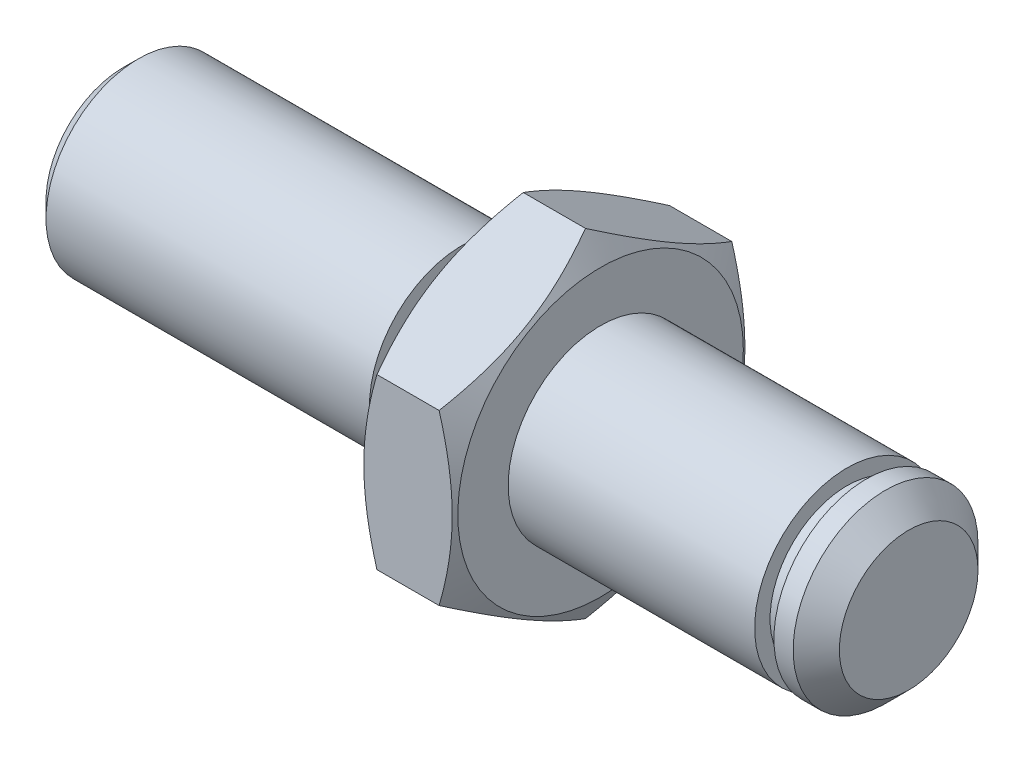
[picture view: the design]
ISO-10303-21;
HEADER;
FILE_DESCRIPTION(('STEP AP214'),'2;1');
FILE_NAME('part.step','',(''),(''),'','','');
FILE_SCHEMA(('AUTOMOTIVE_DESIGN { 1 0 10303 214 1 1 1 1 }'));
ENDSEC;
DATA;
#1=APPLICATION_CONTEXT('core data for automotive mechanical design processes');
#2=APPLICATION_PROTOCOL_DEFINITION('international standard','automotive_design',2000,#1);
#3=PRODUCT_CONTEXT('',#1,'mechanical');
#4=PRODUCT('Part','Part','',(#3));
#5=PRODUCT_RELATED_PRODUCT_CATEGORY('part','',(#4));
#6=PRODUCT_DEFINITION_FORMATION('','',#4);
#7=PRODUCT_DEFINITION_CONTEXT('part definition',#1,'design');
#8=PRODUCT_DEFINITION('design','',#6,#7);
#9=PRODUCT_DEFINITION_SHAPE('','',#8);
#10=(LENGTH_UNIT() NAMED_UNIT(*) SI_UNIT(.MILLI.,.METRE.));
#11=(NAMED_UNIT(*) PLANE_ANGLE_UNIT() SI_UNIT($,.RADIAN.));
#12=(NAMED_UNIT(*) SI_UNIT($,.STERADIAN.) SOLID_ANGLE_UNIT());
#13=UNCERTAINTY_MEASURE_WITH_UNIT(LENGTH_MEASURE(1.E-05),#10,'distance_accuracy_value','');
#14=(GEOMETRIC_REPRESENTATION_CONTEXT(3) GLOBAL_UNCERTAINTY_ASSIGNED_CONTEXT((#13)) GLOBAL_UNIT_ASSIGNED_CONTEXT((#10,
#11,#12)) REPRESENTATION_CONTEXT('',''));
#15=CARTESIAN_POINT('',(0.,0.,0.));
#16=DIRECTION('',(0.,0.,1.));
#17=DIRECTION('',(1.,0.,0.));
#18=AXIS2_PLACEMENT_3D('',#15,#16,#17);
#19=CARTESIAN_POINT('',(31.,0.,0.));
#20=DIRECTION('',(-1.,0.,0.));
#21=DIRECTION('',(0.,0.,1.));
#22=AXIS2_PLACEMENT_3D('',#19,#20,#21);
#23=CONICAL_SURFACE('',#22,9.26794919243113,1.0471975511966);
#24=CARTESIAN_POINT('',(31.,0.,0.));
#25=DIRECTION('',(1.,0.,0.));
#26=DIRECTION('',(0.,0.,-1.));
#27=AXIS2_PLACEMENT_3D('',#24,#25,#26);
#28=CIRCLE('',#27,9.26794919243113);
#29=CARTESIAN_POINT('',(31.,0.,-9.26794919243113));
#30=VERTEX_POINT('',#29);
#31=EDGE_CURVE('E254',#30,#30,#28,.T.);
#32=ORIENTED_EDGE('',*,*,#31,.F.);
#33=EDGE_LOOP('',(#32));
#34=FACE_BOUND('',#33,.T.);
#35=CARTESIAN_POINT('',(30.0174529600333,-5.4847120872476,9.5002));
#36=CARTESIAN_POINT('',(30.0870519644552,-5.60528058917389,9.2913692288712));
#37=CARTESIAN_POINT('',(30.1534920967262,-5.72629863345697,9.08175982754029));
#38=CARTESIAN_POINT('',(30.2791781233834,-5.96930519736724,8.66086011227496));
#39=CARTESIAN_POINT('',(30.3384216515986,-6.09129402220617,8.44956926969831));
#40=CARTESIAN_POINT('',(30.5042108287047,-6.45922610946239,7.81229220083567));
#41=CARTESIAN_POINT('',(30.598510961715,-6.70662183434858,7.38379023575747));
#42=CARTESIAN_POINT('',(30.7090866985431,-7.07683821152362,6.74255666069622));
#43=CARTESIAN_POINT('',(30.7405855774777,-7.19855281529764,6.5317407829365));
#44=CARTESIAN_POINT('',(30.7934072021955,-7.44254555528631,6.10913296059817));
#45=CARTESIAN_POINT('',(30.8147297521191,-7.56482370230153,5.89734099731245));
#46=CARTESIAN_POINT('',(30.8466523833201,-7.80958396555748,5.4734037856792));
#47=CARTESIAN_POINT('',(30.8572652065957,-7.93206566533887,5.26125925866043));
#48=CARTESIAN_POINT('',(30.8675428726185,-8.17714220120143,4.83677424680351));
#49=CARTESIAN_POINT('',(30.867208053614,-8.29973703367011,4.62443376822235));
#50=CARTESIAN_POINT('',(30.8563520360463,-8.5289310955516,4.22745800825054));
#51=CARTESIAN_POINT('',(30.8471551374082,-8.63554650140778,4.04279470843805));
#52=CARTESIAN_POINT('',(30.8206600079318,-8.84852796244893,3.67389999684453));
#53=CARTESIAN_POINT('',(30.8033612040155,-8.95489399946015,3.48966861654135));
#54=CARTESIAN_POINT('',(30.7397209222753,-9.27357996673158,2.93768832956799));
#55=CARTESIAN_POINT('',(30.6816435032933,-9.48533580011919,2.57091646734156));
#56=CARTESIAN_POINT('',(30.5364493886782,-9.91109368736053,1.83348217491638));
#57=CARTESIAN_POINT('',(30.448717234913,-10.1250414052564,1.46291385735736));
#58=CARTESIAN_POINT('',(30.2496016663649,-10.5497463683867,0.727303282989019));
#59=CARTESIAN_POINT('',(30.1382650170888,-10.7605090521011,0.362251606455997));
#60=CARTESIAN_POINT('',(30.0174529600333,-10.9697705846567,-0.000200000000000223));
#61=B_SPLINE_CURVE_WITH_KNOTS('',3,(#35,#36,#37,#38,#39,#40,#41,#42,#43,#44,#45,#46,#47,#48,#49,
#50,#51,#52,#53,#54,#55,#56,#57,#58,#59,#60),.UNSPECIFIED.,.F.,.F.,(4,2,2,2,2,2,2,2,2,2,2,2,4),
(0.,0.752880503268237,1.50600787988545,3.0154687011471,3.75167336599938,4.48789219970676,
5.22323407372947,5.95855322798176,6.59868084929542,7.23885375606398,8.52010929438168,
9.82978009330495,11.1368800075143),.UNSPECIFIED.);
#62=CARTESIAN_POINT('',(30.0175196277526,-5.48482755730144,9.49999999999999));
#63=VERTEX_POINT('',#62);
#64=CARTESIAN_POINT('',(30.0175196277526,-10.9696551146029,0.));
#65=VERTEX_POINT('',#64);
#66=EDGE_CURVE('E48',#63,#65,#61,.T.);
#67=ORIENTED_EDGE('',*,*,#66,.T.);
#68=CARTESIAN_POINT('',(30.0174529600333,-10.9697705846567,0.000199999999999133));
#69=CARTESIAN_POINT('',(30.0870519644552,-10.8492020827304,-0.208630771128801));
#70=CARTESIAN_POINT('',(30.1534920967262,-10.7281840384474,-0.41824017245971));
#71=CARTESIAN_POINT('',(30.2791781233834,-10.4851774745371,-0.839139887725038));
#72=CARTESIAN_POINT('',(30.3384216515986,-10.3631886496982,-1.05043073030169));
#73=CARTESIAN_POINT('',(30.5042108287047,-9.99525656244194,-1.68770779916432));
#74=CARTESIAN_POINT('',(30.598510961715,-9.74786083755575,-2.11620976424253));
#75=CARTESIAN_POINT('',(30.7090866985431,-9.37764446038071,-2.75744333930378));
#76=CARTESIAN_POINT('',(30.7405855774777,-9.25592985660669,-2.96825921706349));
#77=CARTESIAN_POINT('',(30.7934072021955,-9.01193711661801,-3.39086703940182));
#78=CARTESIAN_POINT('',(30.8147297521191,-8.8896589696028,-3.60265900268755));
#79=CARTESIAN_POINT('',(30.8466523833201,-8.64489870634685,-4.0265962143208));
#80=CARTESIAN_POINT('',(30.8572652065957,-8.52241700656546,-4.23874074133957));
#81=CARTESIAN_POINT('',(30.8675428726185,-8.2773404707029,-4.66322575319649));
#82=CARTESIAN_POINT('',(30.867208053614,-8.15474563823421,-4.87556623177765));
#83=CARTESIAN_POINT('',(30.8563520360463,-7.92555157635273,-5.27254199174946));
#84=CARTESIAN_POINT('',(30.8471551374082,-7.81893617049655,-5.45720529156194));
#85=CARTESIAN_POINT('',(30.8206600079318,-7.6059547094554,-5.82610000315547));
#86=CARTESIAN_POINT('',(30.8033612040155,-7.49958867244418,-6.01033138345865));
#87=CARTESIAN_POINT('',(30.7397209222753,-7.18090270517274,-6.56231167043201));
#88=CARTESIAN_POINT('',(30.6816435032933,-6.96914687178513,-6.92908353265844));
#89=CARTESIAN_POINT('',(30.5364493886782,-6.5433889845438,-7.66651782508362));
#90=CARTESIAN_POINT('',(30.448717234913,-6.32944126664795,-8.03708614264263));
#91=CARTESIAN_POINT('',(30.2496016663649,-5.90473630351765,-8.77269671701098));
#92=CARTESIAN_POINT('',(30.1382650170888,-5.69397361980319,-9.137748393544));
#93=CARTESIAN_POINT('',(30.0174529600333,-5.48471208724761,-9.5002));
#94=B_SPLINE_CURVE_WITH_KNOTS('',3,(#68,#69,#70,#71,#72,#73,#74,#75,#76,#77,#78,#79,#80,#81,#82,
#83,#84,#85,#86,#87,#88,#89,#90,#91,#92,#93),.UNSPECIFIED.,.F.,.F.,(4,2,2,2,2,2,2,2,2,2,2,2,4),
(0.,0.752880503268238,1.50600787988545,3.0154687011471,3.75167336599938,4.48789219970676,
5.22323407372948,5.95855322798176,6.59868084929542,7.23885375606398,8.52010929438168,
9.82978009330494,11.1368800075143),.UNSPECIFIED.);
#95=CARTESIAN_POINT('',(30.0175196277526,-5.48482755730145,-9.5));
#96=VERTEX_POINT('',#95);
#97=EDGE_CURVE('E11',#65,#96,#94,.T.);
#98=ORIENTED_EDGE('',*,*,#97,.T.);
#99=CARTESIAN_POINT('',(26.3278254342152,-14.530424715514,-9.5));
#100=CARTESIAN_POINT('',(26.4285687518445,-14.3219433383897,-9.5));
#101=CARTESIAN_POINT('',(26.5287893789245,-14.1132095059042,-9.5));
#102=CARTESIAN_POINT('',(26.7280652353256,-13.6951836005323,-9.5));
#103=CARTESIAN_POINT('',(26.8271204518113,-13.4858915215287,-9.5));
#104=CARTESIAN_POINT('',(27.1223867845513,-12.8570363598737,-9.5));
#105=CARTESIAN_POINT('',(27.3166656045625,-12.4365624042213,-9.5));
#106=CARTESIAN_POINT('',(27.6999280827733,-11.5902889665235,-9.5));
#107=CARTESIAN_POINT('',(27.8888749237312,-11.1644727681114,-9.5));
#108=CARTESIAN_POINT('',(28.2586328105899,-10.3093352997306,-9.5));
#109=CARTESIAN_POINT('',(28.4394442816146,-9.88001421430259,-9.5));
#110=CARTESIAN_POINT('',(28.7928780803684,-9.01192846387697,-9.5));
#111=CARTESIAN_POINT('',(28.9653748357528,-8.57311238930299,-9.5));
#112=CARTESIAN_POINT('',(29.2968184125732,-7.69029988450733,-9.5));
#113=CARTESIAN_POINT('',(29.4557637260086,-7.24630288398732,-9.5));
#114=CARTESIAN_POINT('',(29.7558208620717,-6.35333393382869,-9.5));
#115=CARTESIAN_POINT('',(29.8969707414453,-5.90437491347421,-9.5));
#116=CARTESIAN_POINT('',(30.1568449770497,-5.0000911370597,-9.5));
#117=CARTESIAN_POINT('',(30.275576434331,-4.54476844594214,-9.5));
#118=CARTESIAN_POINT('',(30.4848321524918,-3.62736382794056,-9.5));
#119=CARTESIAN_POINT('',(30.5753480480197,-3.16527993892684,-9.5));
#120=CARTESIAN_POINT('',(30.6854186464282,-2.46810217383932,-9.5));
#121=CARTESIAN_POINT('',(30.7178273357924,-2.23500583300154,-9.5));
#122=CARTESIAN_POINT('',(30.7734391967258,-1.76772497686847,-9.5));
#123=CARTESIAN_POINT('',(30.7966432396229,-1.533540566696,-9.5));
#124=CARTESIAN_POINT('',(30.8332219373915,-1.06587755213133,-9.5));
#125=CARTESIAN_POINT('',(30.8466572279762,-0.832403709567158,-9.5));
#126=CARTESIAN_POINT('',(30.8636276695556,-0.365097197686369,-9.5));
#127=CARTESIAN_POINT('',(30.867162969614,-0.131264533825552,-9.5));
#128=CARTESIAN_POINT('',(30.8642492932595,0.336274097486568,-9.5));
#129=CARTESIAN_POINT('',(30.8578031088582,0.569980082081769,-9.5));
#130=CARTESIAN_POINT('',(30.8350863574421,1.03691732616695,-9.5));
#131=CARTESIAN_POINT('',(30.8188152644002,1.27014855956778,-9.5));
#132=CARTESIAN_POINT('',(30.7677796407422,1.83577635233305,-9.5));
#133=CARTESIAN_POINT('',(30.7280735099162,2.16773568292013,-9.5));
#134=CARTESIAN_POINT('',(30.6309725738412,2.82904294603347,-9.5));
#135=CARTESIAN_POINT('',(30.5735751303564,3.15839048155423,-9.5));
#136=CARTESIAN_POINT('',(30.3777256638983,4.14309533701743,-9.5));
#137=CARTESIAN_POINT('',(30.2157474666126,4.79382711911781,-9.5));
#138=CARTESIAN_POINT('',(29.9365826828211,5.76718145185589,-9.5));
#139=CARTESIAN_POINT('',(29.8361342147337,6.09489303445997,-9.5));
#140=CARTESIAN_POINT('',(29.6252534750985,6.74715044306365,-9.5));
#141=CARTESIAN_POINT('',(29.5148203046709,7.0716959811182,-9.5));
#142=CARTESIAN_POINT('',(29.2863341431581,7.71600141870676,-9.5));
#143=CARTESIAN_POINT('',(29.1683276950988,8.03577799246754,-9.5));
#144=CARTESIAN_POINT('',(28.9255004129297,8.67261160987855,-9.5));
#145=CARTESIAN_POINT('',(28.8006819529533,8.98966955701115,-9.5));
#146=CARTESIAN_POINT('',(28.6730955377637,9.30558311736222,-9.5));
#147=B_SPLINE_CURVE_WITH_KNOTS('',3,(#99,#100,#101,#102,#103,#104,#105,#106,#107,#108,#109,#110,
#111,#112,#113,#114,#115,#116,#117,#118,#119,#120,#121,#122,#123,#124,#125,#126,#127,#128,#129,
#130,#131,#132,#133,#134,#135,#136,#137,#138,#139,#140,#141,#142,#143,#144,#145,#146),
.UNSPECIFIED.,.F.,.F.,(4,2,2,2,2,2,2,2,2,2,2,2,2,2,2,2,2,2,2,2,2,2,2,4),(0.,0.694637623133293,
1.38928288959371,2.77880027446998,4.17629754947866,5.57372171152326,6.98805594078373,
8.40254735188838,9.81396052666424,11.2249258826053,12.6363091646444,13.3421715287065,
14.0479670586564,14.7493433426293,15.4507090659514,16.1518786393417,16.8530857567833,
17.8554925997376,18.8580490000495,20.867027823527,21.8952298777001,22.9235245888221,
23.9460134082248,24.9681481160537),.UNSPECIFIED.);
#148=CARTESIAN_POINT('',(30.0175196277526,5.48482755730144,-9.5));
#149=VERTEX_POINT('',#148);
#150=EDGE_CURVE('E149',#96,#149,#147,.T.);
#151=ORIENTED_EDGE('',*,*,#150,.T.);
#152=CARTESIAN_POINT('',(30.0174529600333,5.4847120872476,-9.5002));
#153=CARTESIAN_POINT('',(30.0870519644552,5.6052805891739,-9.2913692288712));
#154=CARTESIAN_POINT('',(30.1534920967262,5.72629863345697,-9.08175982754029));
#155=CARTESIAN_POINT('',(30.2791781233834,5.96930519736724,-8.66086011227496));
#156=CARTESIAN_POINT('',(30.3384216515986,6.09129402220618,-8.44956926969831));
#157=CARTESIAN_POINT('',(30.5042108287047,6.45922610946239,-7.81229220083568));
#158=CARTESIAN_POINT('',(30.598510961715,6.70662183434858,-7.38379023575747));
#159=CARTESIAN_POINT('',(30.7090866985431,7.07683821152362,-6.74255666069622));
#160=CARTESIAN_POINT('',(30.7405855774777,7.19855281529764,-6.53174078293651));
#161=CARTESIAN_POINT('',(30.7934072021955,7.44254555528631,-6.10913296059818));
#162=CARTESIAN_POINT('',(30.8147297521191,7.56482370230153,-5.89734099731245));
#163=CARTESIAN_POINT('',(30.8466523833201,7.80958396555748,-5.4734037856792));
#164=CARTESIAN_POINT('',(30.8572652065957,7.93206566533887,-5.26125925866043));
#165=CARTESIAN_POINT('',(30.8675428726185,8.17714220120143,-4.83677424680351));
#166=CARTESIAN_POINT('',(30.867208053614,8.29973703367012,-4.62443376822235));
#167=CARTESIAN_POINT('',(30.8563520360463,8.5289310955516,-4.22745800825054));
#168=CARTESIAN_POINT('',(30.8471551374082,8.63554650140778,-4.04279470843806));
#169=CARTESIAN_POINT('',(30.8206600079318,8.84852796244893,-3.67389999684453));
#170=CARTESIAN_POINT('',(30.8033612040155,8.95489399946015,-3.48966861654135));
#171=CARTESIAN_POINT('',(30.7397209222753,9.27357996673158,-2.93768832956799));
#172=CARTESIAN_POINT('',(30.6816435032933,9.48533580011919,-2.57091646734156));
#173=CARTESIAN_POINT('',(30.5364493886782,9.91109368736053,-1.83348217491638));
#174=CARTESIAN_POINT('',(30.448717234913,10.1250414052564,-1.46291385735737));
#175=CARTESIAN_POINT('',(30.2496016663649,10.5497463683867,-0.727303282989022));
#176=CARTESIAN_POINT('',(30.1382650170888,10.7605090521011,-0.362251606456));
#177=CARTESIAN_POINT('',(30.0174529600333,10.9697705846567,0.000199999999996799));
#178=B_SPLINE_CURVE_WITH_KNOTS('',3,(#152,#153,#154,#155,#156,#157,#158,#159,#160,#161,#162,
#163,#164,#165,#166,#167,#168,#169,#170,#171,#172,#173,#174,#175,#176,#177),.UNSPECIFIED.,.F.,
.F.,(4,2,2,2,2,2,2,2,2,2,2,2,4),(0.,0.752880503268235,1.50600787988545,3.0154687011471,
3.75167336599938,4.48789219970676,5.22323407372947,5.95855322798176,6.59868084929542,
7.23885375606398,8.52010929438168,9.82978009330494,11.1368800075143),.UNSPECIFIED.);
#179=CARTESIAN_POINT('',(30.0175196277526,10.9696551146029,0.));
#180=VERTEX_POINT('',#179);
#181=EDGE_CURVE('E103',#149,#180,#178,.T.);
#182=ORIENTED_EDGE('',*,*,#181,.T.);
#183=CARTESIAN_POINT('',(30.0174529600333,10.9697705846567,-0.000200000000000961));
#184=CARTESIAN_POINT('',(30.0870519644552,10.8492020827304,0.208630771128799));
#185=CARTESIAN_POINT('',(30.1534920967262,10.7281840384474,0.418240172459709));
#186=CARTESIAN_POINT('',(30.2791781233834,10.4851774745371,0.839139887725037));
#187=CARTESIAN_POINT('',(30.3384216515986,10.3631886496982,1.05043073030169));
#188=CARTESIAN_POINT('',(30.5042108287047,9.99525656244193,1.68770779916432));
#189=CARTESIAN_POINT('',(30.5985109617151,9.74786083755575,2.11620976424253));
#190=CARTESIAN_POINT('',(30.7090866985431,9.37764446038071,2.75744333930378));
#191=CARTESIAN_POINT('',(30.7405855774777,9.25592985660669,2.96825921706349));
#192=CARTESIAN_POINT('',(30.7934072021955,9.01193711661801,3.39086703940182));
#193=CARTESIAN_POINT('',(30.8147297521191,8.8896589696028,3.60265900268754));
#194=CARTESIAN_POINT('',(30.8466523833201,8.64489870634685,4.0265962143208));
#195=CARTESIAN_POINT('',(30.8572652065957,8.52241700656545,4.23874074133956));
#196=CARTESIAN_POINT('',(30.8675428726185,8.2773404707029,4.66322575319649));
#197=CARTESIAN_POINT('',(30.867208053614,8.15474563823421,4.87556623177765));
#198=CARTESIAN_POINT('',(30.8563520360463,7.92555157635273,5.27254199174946));
#199=CARTESIAN_POINT('',(30.8471551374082,7.81893617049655,5.45720529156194));
#200=CARTESIAN_POINT('',(30.8206600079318,7.6059547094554,5.82610000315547));
#201=CARTESIAN_POINT('',(30.8033612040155,7.49958867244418,6.01033138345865));
#202=CARTESIAN_POINT('',(30.7397209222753,7.18090270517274,6.56231167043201));
#203=CARTESIAN_POINT('',(30.6816435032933,6.96914687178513,6.92908353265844));
#204=CARTESIAN_POINT('',(30.5364493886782,6.5433889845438,7.66651782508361));
#205=CARTESIAN_POINT('',(30.448717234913,6.32944126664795,8.03708614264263));
#206=CARTESIAN_POINT('',(30.2496016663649,5.90473630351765,8.77269671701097));
#207=CARTESIAN_POINT('',(30.1382650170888,5.69397361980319,9.137748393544));
#208=CARTESIAN_POINT('',(30.0174529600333,5.4847120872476,9.50019999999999));
#209=B_SPLINE_CURVE_WITH_KNOTS('',3,(#183,#184,#185,#186,#187,#188,#189,#190,#191,#192,#193,
#194,#195,#196,#197,#198,#199,#200,#201,#202,#203,#204,#205,#206,#207,#208),.UNSPECIFIED.,.F.,
.F.,(4,2,2,2,2,2,2,2,2,2,2,2,4),(0.,0.752880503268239,1.50600787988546,3.01546870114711,
3.75167336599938,4.48789219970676,5.22323407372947,5.95855322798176,6.59868084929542,
7.23885375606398,8.52010929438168,9.82978009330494,11.1368800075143),.UNSPECIFIED.);
#210=CARTESIAN_POINT('',(30.0175196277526,5.48482755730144,9.49999999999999));
#211=VERTEX_POINT('',#210);
#212=EDGE_CURVE('E148',#180,#211,#209,.T.);
#213=ORIENTED_EDGE('',*,*,#212,.T.);
#214=CARTESIAN_POINT('',(26.3278254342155,-14.5304247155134,9.49999999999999));
#215=CARTESIAN_POINT('',(26.4285687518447,-14.3219433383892,9.49999999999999));
#216=CARTESIAN_POINT('',(26.5287893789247,-14.1132095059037,9.49999999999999));
#217=CARTESIAN_POINT('',(26.7280652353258,-13.6951836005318,9.49999999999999));
#218=CARTESIAN_POINT('',(26.8271204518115,-13.4858915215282,9.49999999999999));
#219=CARTESIAN_POINT('',(27.1223867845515,-12.8570363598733,9.49999999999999));
#220=CARTESIAN_POINT('',(27.3166656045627,-12.4365624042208,9.49999999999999));
#221=CARTESIAN_POINT('',(27.6999280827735,-11.5902889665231,9.49999999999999));
#222=CARTESIAN_POINT('',(27.8888749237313,-11.164472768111,9.49999999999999));
#223=CARTESIAN_POINT('',(28.2586328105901,-10.3093352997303,9.49999999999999));
#224=CARTESIAN_POINT('',(28.4394442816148,-9.88001421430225,9.49999999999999));
#225=CARTESIAN_POINT('',(28.7928780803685,-9.01192846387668,9.49999999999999));
#226=CARTESIAN_POINT('',(28.9653748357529,-8.57311238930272,9.49999999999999));
#227=CARTESIAN_POINT('',(29.2968184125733,-7.6902998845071,9.49999999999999));
#228=CARTESIAN_POINT('',(29.4557637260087,-7.2463028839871,9.49999999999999));
#229=CARTESIAN_POINT('',(29.7558208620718,-6.35333393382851,9.49999999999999));
#230=CARTESIAN_POINT('',(29.8969707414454,-5.90437491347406,9.49999999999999));
#231=CARTESIAN_POINT('',(30.1568449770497,-5.00009113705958,9.49999999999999));
#232=CARTESIAN_POINT('',(30.2755764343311,-4.54476844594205,9.49999999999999));
#233=CARTESIAN_POINT('',(30.4848321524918,-3.62736382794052,9.49999999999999));
#234=CARTESIAN_POINT('',(30.5753480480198,-3.16527993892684,9.49999999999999));
#235=CARTESIAN_POINT('',(30.6854186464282,-2.46810217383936,9.49999999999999));
#236=CARTESIAN_POINT('',(30.7178273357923,-2.2350058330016,9.49999999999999));
#237=CARTESIAN_POINT('',(30.7734391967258,-1.76772497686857,9.49999999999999));
#238=CARTESIAN_POINT('',(30.7966432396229,-1.53354056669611,9.49999999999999));
#239=CARTESIAN_POINT('',(30.8332219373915,-1.06587755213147,9.49999999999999));
#240=CARTESIAN_POINT('',(30.8466572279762,-0.832403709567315,9.49999999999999));
#241=CARTESIAN_POINT('',(30.8636276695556,-0.365097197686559,9.49999999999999));
#242=CARTESIAN_POINT('',(30.867162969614,-0.131264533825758,9.49999999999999));
#243=CARTESIAN_POINT('',(30.8642492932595,0.33627409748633,9.49999999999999));
#244=CARTESIAN_POINT('',(30.8578031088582,0.569980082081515,9.49999999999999));
#245=CARTESIAN_POINT('',(30.8350863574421,1.03691732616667,9.49999999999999));
#246=CARTESIAN_POINT('',(30.8188152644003,1.27014855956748,9.49999999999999));
#247=CARTESIAN_POINT('',(30.7677796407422,1.83577635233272,9.49999999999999));
#248=CARTESIAN_POINT('',(30.7280735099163,2.16773568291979,9.49999999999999));
#249=CARTESIAN_POINT('',(30.6309725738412,2.82904294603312,9.49999999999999));
#250=CARTESIAN_POINT('',(30.5735751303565,3.15839048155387,9.49999999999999));
#251=CARTESIAN_POINT('',(30.3777256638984,4.14309533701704,9.49999999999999));
#252=CARTESIAN_POINT('',(30.2157474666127,4.79382711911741,9.49999999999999));
#253=CARTESIAN_POINT('',(29.9365826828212,5.76718145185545,9.49999999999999));
#254=CARTESIAN_POINT('',(29.8361342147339,6.09489303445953,9.49999999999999));
#255=CARTESIAN_POINT('',(29.6252534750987,6.74715044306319,9.49999999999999));
#256=CARTESIAN_POINT('',(29.514820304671,7.07169598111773,9.49999999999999));
#257=CARTESIAN_POINT('',(29.2863341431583,7.71600141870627,9.49999999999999));
#258=CARTESIAN_POINT('',(29.168327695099,8.03577799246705,9.49999999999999));
#259=CARTESIAN_POINT('',(28.9255004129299,8.67261160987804,9.49999999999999));
#260=CARTESIAN_POINT('',(28.8006819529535,8.98966955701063,9.49999999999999));
#261=CARTESIAN_POINT('',(28.6730955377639,9.30558311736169,9.49999999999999));
#262=B_SPLINE_CURVE_WITH_KNOTS('',3,(#214,#215,#216,#217,#218,#219,#220,#221,#222,#223,#224,
#225,#226,#227,#228,#229,#230,#231,#232,#233,#234,#235,#236,#237,#238,#239,#240,#241,#242,#243,
#244,#245,#246,#247,#248,#249,#250,#251,#252,#253,#254,#255,#256,#257,#258,#259,#260,#261),
.UNSPECIFIED.,.F.,.F.,(4,2,2,2,2,2,2,2,2,2,2,2,2,2,2,2,2,2,2,2,2,2,2,4),(0.,0.694637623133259,
1.38928288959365,2.77880027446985,4.17629754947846,5.573721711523,6.9880559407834,
8.40254735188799,9.81396052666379,11.2249258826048,12.6363091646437,13.3421715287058,
14.0479670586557,14.7493433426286,15.4507090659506,16.1518786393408,16.8530857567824,
17.8554925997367,18.8580490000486,20.867027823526,21.8952298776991,22.923524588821,
23.9460134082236,24.9681481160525),.UNSPECIFIED.);
#263=EDGE_CURVE('E171',#211,#63,#262,.F.);
#264=ORIENTED_EDGE('',*,*,#263,.T.);
#265=EDGE_LOOP('',(#67,#98,#151,#182,#213,#264));
#266=FACE_BOUND('',#265,.T.);
#267=ADVANCED_FACE('F34',(#34,#266),#23,.T.);
#268=CARTESIAN_POINT('',(31.,9.26794919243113,0.));
#269=DIRECTION('',(1.,0.,0.));
#270=DIRECTION('',(0.,0.,-1.));
#271=AXIS2_PLACEMENT_3D('',#268,#269,#270);
#272=PLANE('',#271);
#273=ORIENTED_EDGE('',*,*,#31,.T.);
#274=EDGE_LOOP('',(#273));
#275=FACE_BOUND('',#274,.T.);
#276=CARTESIAN_POINT('',(31.,0.,0.));
#277=DIRECTION('',(1.,0.,0.));
#278=DIRECTION('',(0.,0.,-1.));
#279=AXIS2_PLACEMENT_3D('',#276,#277,#278);
#280=CIRCLE('',#279,6.);
#281=CARTESIAN_POINT('',(31.,0.,-6.));
#282=VERTEX_POINT('',#281);
#283=EDGE_CURVE('E248',#282,#282,#280,.T.);
#284=ORIENTED_EDGE('',*,*,#283,.F.);
#285=EDGE_LOOP('',(#284));
#286=FACE_BOUND('',#285,.T.);
#287=ADVANCED_FACE('F163',(#275,#286),#272,.T.);
#288=CARTESIAN_POINT('',(0.,0.,0.));
#289=DIRECTION('',(1.,0.,0.));
#290=DIRECTION('',(0.,0.,-1.));
#291=AXIS2_PLACEMENT_3D('',#288,#289,#290);
#292=CYLINDRICAL_SURFACE('',#291,6.);
#293=ORIENTED_EDGE('',*,*,#283,.T.);
#294=EDGE_LOOP('',(#293));
#295=FACE_BOUND('',#294,.T.);
#296=CARTESIAN_POINT('',(47.,0.,0.));
#297=DIRECTION('',(1.,0.,0.));
#298=DIRECTION('',(0.,0.,-1.));
#299=AXIS2_PLACEMENT_3D('',#296,#297,#298);
#300=CIRCLE('',#299,6.);
#301=CARTESIAN_POINT('',(47.,0.,-6.));
#302=VERTEX_POINT('',#301);
#303=EDGE_CURVE('E251',#302,#302,#300,.T.);
#304=ORIENTED_EDGE('',*,*,#303,.F.);
#305=EDGE_LOOP('',(#304));
#306=FACE_BOUND('',#305,.T.);
#307=ADVANCED_FACE('F237',(#295,#306),#292,.T.);
#308=CARTESIAN_POINT('',(47.,6.,0.));
#309=DIRECTION('',(1.,0.,0.));
#310=DIRECTION('',(0.,0.,-1.));
#311=AXIS2_PLACEMENT_3D('',#308,#309,#310);
#312=PLANE('',#311);
#313=ORIENTED_EDGE('',*,*,#303,.T.);
#314=EDGE_LOOP('',(#313));
#315=FACE_BOUND('',#314,.T.);
#316=CARTESIAN_POINT('',(47.,0.,0.));
#317=DIRECTION('',(1.,0.,0.));
#318=DIRECTION('',(0.,0.,-1.));
#319=AXIS2_PLACEMENT_3D('',#316,#317,#318);
#320=CIRCLE('',#319,5.);
#321=CARTESIAN_POINT('',(47.,0.,-5.));
#322=VERTEX_POINT('',#321);
#323=EDGE_CURVE('E252',#322,#322,#320,.T.);
#324=ORIENTED_EDGE('',*,*,#323,.F.);
#325=EDGE_LOOP('',(#324));
#326=FACE_BOUND('',#325,.T.);
#327=ADVANCED_FACE('F234',(#315,#326),#312,.T.);
#328=CARTESIAN_POINT('',(0.,0.,0.));
#329=DIRECTION('',(1.,0.,0.));
#330=DIRECTION('',(0.,0.,-1.));
#331=AXIS2_PLACEMENT_3D('',#328,#329,#330);
#332=CYLINDRICAL_SURFACE('',#331,5.);
#333=ORIENTED_EDGE('',*,*,#323,.T.);
#334=EDGE_LOOP('',(#333));
#335=FACE_BOUND('',#334,.T.);
#336=CARTESIAN_POINT('',(48.25,0.,0.));
#337=DIRECTION('',(1.,0.,0.));
#338=DIRECTION('',(0.,0.,-1.));
#339=AXIS2_PLACEMENT_3D('',#336,#337,#338);
#340=CIRCLE('',#339,5.);
#341=CARTESIAN_POINT('',(48.25,0.,-5.));
#342=VERTEX_POINT('',#341);
#343=EDGE_CURVE('E257',#342,#342,#340,.T.);
#344=ORIENTED_EDGE('',*,*,#343,.F.);
#345=EDGE_LOOP('',(#344));
#346=FACE_BOUND('',#345,.T.);
#347=ADVANCED_FACE('F230',(#335,#346),#332,.T.);
#348=CARTESIAN_POINT('',(48.25,5.,0.));
#349=DIRECTION('',(-1.,0.,0.));
#350=DIRECTION('',(0.,0.,1.));
#351=AXIS2_PLACEMENT_3D('',#348,#349,#350);
#352=PLANE('',#351);
#353=ORIENTED_EDGE('',*,*,#343,.T.);
#354=EDGE_LOOP('',(#353));
#355=FACE_BOUND('',#354,.T.);
#356=CARTESIAN_POINT('',(48.25,0.,0.));
#357=DIRECTION('',(1.,0.,0.));
#358=DIRECTION('',(0.,0.,-1.));
#359=AXIS2_PLACEMENT_3D('',#356,#357,#358);
#360=CIRCLE('',#359,6.);
#361=CARTESIAN_POINT('',(48.25,0.,-6.));
#362=VERTEX_POINT('',#361);
#363=EDGE_CURVE('E470',#362,#362,#360,.T.);
#364=ORIENTED_EDGE('',*,*,#363,.F.);
#365=EDGE_LOOP('',(#364));
#366=FACE_BOUND('',#365,.T.);
#367=ADVANCED_FACE('F226',(#355,#366),#352,.T.);
#368=CARTESIAN_POINT('',(0.,0.,0.));
#369=DIRECTION('',(1.,0.,0.));
#370=DIRECTION('',(0.,0.,-1.));
#371=AXIS2_PLACEMENT_3D('',#368,#369,#370);
#372=CYLINDRICAL_SURFACE('',#371,6.);
#373=ORIENTED_EDGE('',*,*,#363,.T.);
#374=EDGE_LOOP('',(#373));
#375=FACE_BOUND('',#374,.T.);
#376=CARTESIAN_POINT('',(49.5,0.,0.));
#377=DIRECTION('',(1.,0.,0.));
#378=DIRECTION('',(0.,0.,-1.));
#379=AXIS2_PLACEMENT_3D('',#376,#377,#378);
#380=CIRCLE('',#379,6.);
#381=CARTESIAN_POINT('',(49.5,0.,-6.));
#382=VERTEX_POINT('',#381);
#383=EDGE_CURVE('E467',#382,#382,#380,.T.);
#384=ORIENTED_EDGE('',*,*,#383,.F.);
#385=EDGE_LOOP('',(#384));
#386=FACE_BOUND('',#385,.T.);
#387=ADVANCED_FACE('F222',(#375,#386),#372,.T.);
#388=CARTESIAN_POINT('',(51.,0.,0.));
#389=DIRECTION('',(-1.,0.,0.));
#390=DIRECTION('',(0.,0.,1.));
#391=AXIS2_PLACEMENT_3D('',#388,#389,#390);
#392=CONICAL_SURFACE('',#391,4.49999999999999,0.785398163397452);
#393=ORIENTED_EDGE('',*,*,#383,.T.);
#394=EDGE_LOOP('',(#393));
#395=FACE_BOUND('',#394,.T.);
#396=CARTESIAN_POINT('',(51.,0.,0.));
#397=DIRECTION('',(1.,0.,0.));
#398=DIRECTION('',(0.,0.,-1.));
#399=AXIS2_PLACEMENT_3D('',#396,#397,#398);
#400=CIRCLE('',#399,4.49999999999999);
#401=CARTESIAN_POINT('',(51.,0.,-4.49999999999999));
#402=VERTEX_POINT('',#401);
#403=EDGE_CURVE('E208',#402,#402,#400,.T.);
#404=ORIENTED_EDGE('',*,*,#403,.F.);
#405=EDGE_LOOP('',(#404));
#406=FACE_BOUND('',#405,.T.);
#407=ADVANCED_FACE('F218',(#395,#406),#392,.T.);
#408=CARTESIAN_POINT('',(51.,0.,0.));
#409=DIRECTION('',(1.,0.,0.));
#410=DIRECTION('',(0.,0.,-1.));
#411=AXIS2_PLACEMENT_3D('',#408,#409,#410);
#412=PLANE('',#411);
#413=ORIENTED_EDGE('',*,*,#403,.T.);
#414=EDGE_LOOP('',(#413));
#415=FACE_BOUND('',#414,.T.);
#416=ADVANCED_FACE('F213',(#415),#412,.T.);
#417=CARTESIAN_POINT('',(0.,-10.9696551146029,0.));
#418=DIRECTION('',(0.,-0.866025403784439,-0.5));
#419=DIRECTION('',(0.,0.5,-0.866025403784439));
#420=AXIS2_PLACEMENT_3D('',#417,#418,#419);
#421=PLANE('',#420);
#422=DIRECTION('',(1.,0.,0.));
#423=VECTOR('',#422,1.);
#424=CARTESIAN_POINT('',(0.,-5.48482755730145,-9.5));
#425=LINE('',#424,#423);
#426=CARTESIAN_POINT('',(25.9824803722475,-5.48482755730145,-9.5));
#427=VERTEX_POINT('',#426);
#428=EDGE_CURVE('E55',#427,#96,#425,.T.);
#429=ORIENTED_EDGE('',*,*,#428,.T.);
#430=ORIENTED_EDGE('',*,*,#97,.F.);
#431=DIRECTION('',(1.,0.,0.));
#432=VECTOR('',#431,1.);
#433=CARTESIAN_POINT('',(0.,-10.9696551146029,0.));
#434=LINE('',#433,#432);
#435=CARTESIAN_POINT('',(25.9824803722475,-10.9696551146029,0.));
#436=VERTEX_POINT('',#435);
#437=EDGE_CURVE('E96',#436,#65,#434,.T.);
#438=ORIENTED_EDGE('',*,*,#437,.F.);
#439=CARTESIAN_POINT('',(25.9825470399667,-5.48471208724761,-9.5002));
#440=CARTESIAN_POINT('',(25.9129480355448,-5.6052805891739,-9.2913692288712));
#441=CARTESIAN_POINT('',(25.8465079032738,-5.72629863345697,-9.08175982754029));
#442=CARTESIAN_POINT('',(25.7208218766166,-5.96930519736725,-8.66086011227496));
#443=CARTESIAN_POINT('',(25.6615783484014,-6.09129402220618,-8.44956926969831));
#444=CARTESIAN_POINT('',(25.4957891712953,-6.4592261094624,-7.81229220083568));
#445=CARTESIAN_POINT('',(25.401489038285,-6.70662183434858,-7.38379023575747));
#446=CARTESIAN_POINT('',(25.2909133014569,-7.07683821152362,-6.74255666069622));
#447=CARTESIAN_POINT('',(25.2594144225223,-7.19855281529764,-6.53174078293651));
#448=CARTESIAN_POINT('',(25.2065927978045,-7.44254555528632,-6.10913296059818));
#449=CARTESIAN_POINT('',(25.1852702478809,-7.56482370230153,-5.89734099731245));
#450=CARTESIAN_POINT('',(25.1533476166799,-7.80958396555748,-5.4734037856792));
#451=CARTESIAN_POINT('',(25.1427347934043,-7.93206566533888,-5.26125925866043));
#452=CARTESIAN_POINT('',(25.1324571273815,-8.17714220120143,-4.83677424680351));
#453=CARTESIAN_POINT('',(25.132791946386,-8.29973703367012,-4.62443376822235));
#454=CARTESIAN_POINT('',(25.1436479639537,-8.5289310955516,-4.22745800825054));
#455=CARTESIAN_POINT('',(25.1528448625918,-8.63554650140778,-4.04279470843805));
#456=CARTESIAN_POINT('',(25.1793399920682,-8.84852796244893,-3.67389999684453));
#457=CARTESIAN_POINT('',(25.1966387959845,-8.95489399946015,-3.48966861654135));
#458=CARTESIAN_POINT('',(25.2602790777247,-9.27357996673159,-2.93768832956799));
#459=CARTESIAN_POINT('',(25.3183564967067,-9.4853358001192,-2.57091646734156));
#460=CARTESIAN_POINT('',(25.4635506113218,-9.91109368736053,-1.83348217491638));
#461=CARTESIAN_POINT('',(25.551282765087,-10.1250414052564,-1.46291385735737));
#462=CARTESIAN_POINT('',(25.7503983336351,-10.5497463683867,-0.727303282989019));
#463=CARTESIAN_POINT('',(25.8617349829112,-10.7605090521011,-0.362251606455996));
#464=CARTESIAN_POINT('',(25.9825470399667,-10.9697705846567,0.000199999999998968));
#465=B_SPLINE_CURVE_WITH_KNOTS('',3,(#439,#440,#441,#442,#443,#444,#445,#446,#447,#448,#449,
#450,#451,#452,#453,#454,#455,#456,#457,#458,#459,#460,#461,#462,#463,#464),.UNSPECIFIED.,.F.,
.F.,(4,2,2,2,2,2,2,2,2,2,2,2,4),(0.,0.752880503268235,1.50600787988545,3.01546870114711,
3.75167336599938,4.48789219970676,5.22323407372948,5.95855322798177,6.59868084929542,
7.23885375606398,8.52010929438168,9.82978009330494,11.1368800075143),.UNSPECIFIED.);
#466=EDGE_CURVE('E198',#427,#436,#465,.T.);
#467=ORIENTED_EDGE('',*,*,#466,.F.);
#468=EDGE_LOOP('',(#429,#430,#438,#467));
#469=FACE_BOUND('',#468,.T.);
#470=ADVANCED_FACE('F186',(#469),#421,.T.);
#471=CARTESIAN_POINT('',(0.,-5.48482755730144,9.49999999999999));
#472=DIRECTION('',(0.,-0.866025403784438,0.5));
#473=DIRECTION('',(0.,-0.5,-0.866025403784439));
#474=AXIS2_PLACEMENT_3D('',#471,#472,#473);
#475=PLANE('',#474);
#476=ORIENTED_EDGE('',*,*,#437,.T.);
#477=ORIENTED_EDGE('',*,*,#66,.F.);
#478=DIRECTION('',(1.,0.,0.));
#479=VECTOR('',#478,1.);
#480=CARTESIAN_POINT('',(0.,-5.48482755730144,9.49999999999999));
#481=LINE('',#480,#479);
#482=CARTESIAN_POINT('',(25.9824803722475,-5.48482755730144,9.49999999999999));
#483=VERTEX_POINT('',#482);
#484=EDGE_CURVE('E290',#483,#63,#481,.T.);
#485=ORIENTED_EDGE('',*,*,#484,.F.);
#486=CARTESIAN_POINT('',(25.9825470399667,-10.9697705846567,-0.000200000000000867));
#487=CARTESIAN_POINT('',(25.9129480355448,-10.8492020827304,0.2086307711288));
#488=CARTESIAN_POINT('',(25.8465079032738,-10.7281840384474,0.418240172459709));
#489=CARTESIAN_POINT('',(25.7208218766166,-10.4851774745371,0.839139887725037));
#490=CARTESIAN_POINT('',(25.6615783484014,-10.3631886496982,1.05043073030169));
#491=CARTESIAN_POINT('',(25.4957891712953,-9.99525656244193,1.68770779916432));
#492=CARTESIAN_POINT('',(25.4014890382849,-9.74786083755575,2.11620976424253));
#493=CARTESIAN_POINT('',(25.2909133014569,-9.37764446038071,2.75744333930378));
#494=CARTESIAN_POINT('',(25.2594144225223,-9.25592985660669,2.96825921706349));
#495=CARTESIAN_POINT('',(25.2065927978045,-9.01193711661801,3.39086703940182));
#496=CARTESIAN_POINT('',(25.1852702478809,-8.8896589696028,3.60265900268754));
#497=CARTESIAN_POINT('',(25.1533476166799,-8.64489870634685,4.0265962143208));
#498=CARTESIAN_POINT('',(25.1427347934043,-8.52241700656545,4.23874074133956));
#499=CARTESIAN_POINT('',(25.1324571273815,-8.2773404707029,4.66322575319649));
#500=CARTESIAN_POINT('',(25.132791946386,-8.15474563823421,4.87556623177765));
#501=CARTESIAN_POINT('',(25.1436479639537,-7.92555157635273,5.27254199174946));
#502=CARTESIAN_POINT('',(25.1528448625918,-7.81893617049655,5.45720529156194));
#503=CARTESIAN_POINT('',(25.1793399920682,-7.6059547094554,5.82610000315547));
#504=CARTESIAN_POINT('',(25.1966387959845,-7.49958867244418,6.01033138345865));
#505=CARTESIAN_POINT('',(25.2602790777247,-7.18090270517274,6.56231167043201));
#506=CARTESIAN_POINT('',(25.3183564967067,-6.96914687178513,6.92908353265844));
#507=CARTESIAN_POINT('',(25.4635506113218,-6.5433889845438,7.66651782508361));
#508=CARTESIAN_POINT('',(25.551282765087,-6.32944126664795,8.03708614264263));
#509=CARTESIAN_POINT('',(25.7503983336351,-5.90473630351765,8.77269671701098));
#510=CARTESIAN_POINT('',(25.8617349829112,-5.69397361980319,9.137748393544));
#511=CARTESIAN_POINT('',(25.9825470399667,-5.4847120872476,9.5002));
#512=B_SPLINE_CURVE_WITH_KNOTS('',3,(#486,#487,#488,#489,#490,#491,#492,#493,#494,#495,#496,
#497,#498,#499,#500,#501,#502,#503,#504,#505,#506,#507,#508,#509,#510,#511),.UNSPECIFIED.,.F.,
.F.,(4,2,2,2,2,2,2,2,2,2,2,2,4),(0.,0.752880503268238,1.50600787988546,3.01546870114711,
3.75167336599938,4.48789219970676,5.22323407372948,5.95855322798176,6.59868084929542,
7.23885375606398,8.52010929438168,9.82978009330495,11.1368800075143),.UNSPECIFIED.);
#513=EDGE_CURVE('E191',#436,#483,#512,.T.);
#514=ORIENTED_EDGE('',*,*,#513,.F.);
#515=EDGE_LOOP('',(#476,#477,#485,#514));
#516=FACE_BOUND('',#515,.T.);
#517=ADVANCED_FACE('F182',(#516),#475,.T.);
#518=CARTESIAN_POINT('',(0.,5.48482755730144,9.49999999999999));
#519=DIRECTION('',(0.,0.,1.));
#520=DIRECTION('',(1.,0.,0.));
#521=AXIS2_PLACEMENT_3D('',#518,#519,#520);
#522=PLANE('',#521);
#523=ORIENTED_EDGE('',*,*,#484,.T.);
#524=ORIENTED_EDGE('',*,*,#263,.F.);
#525=DIRECTION('',(1.,0.,0.));
#526=VECTOR('',#525,1.);
#527=CARTESIAN_POINT('',(0.,5.48482755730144,9.49999999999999));
#528=LINE('',#527,#526);
#529=CARTESIAN_POINT('',(25.9824803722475,5.48482755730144,9.49999999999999));
#530=VERTEX_POINT('',#529);
#531=EDGE_CURVE('E287',#530,#211,#528,.T.);
#532=ORIENTED_EDGE('',*,*,#531,.F.);
#533=CARTESIAN_POINT('',(29.6721745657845,-14.5304247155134,9.49999999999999));
#534=CARTESIAN_POINT('',(29.5714312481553,-14.3219433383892,9.49999999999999));
#535=CARTESIAN_POINT('',(29.4712106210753,-14.1132095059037,9.49999999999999));
#536=CARTESIAN_POINT('',(29.2719347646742,-13.6951836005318,9.49999999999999));
#537=CARTESIAN_POINT('',(29.1728795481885,-13.4858915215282,9.49999999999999));
#538=CARTESIAN_POINT('',(28.8776132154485,-12.8570363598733,9.49999999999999));
#539=CARTESIAN_POINT('',(28.6833343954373,-12.4365624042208,9.49999999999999));
#540=CARTESIAN_POINT('',(28.3000719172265,-11.5902889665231,9.49999999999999));
#541=CARTESIAN_POINT('',(28.1111250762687,-11.164472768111,9.49999999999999));
#542=CARTESIAN_POINT('',(27.7413671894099,-10.3093352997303,9.49999999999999));
#543=CARTESIAN_POINT('',(27.5605557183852,-9.88001421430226,9.49999999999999));
#544=CARTESIAN_POINT('',(27.2071219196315,-9.01192846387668,9.49999999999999));
#545=CARTESIAN_POINT('',(27.0346251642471,-8.57311238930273,9.49999999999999));
#546=CARTESIAN_POINT('',(26.7031815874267,-7.6902998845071,9.49999999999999));
#547=CARTESIAN_POINT('',(26.5442362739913,-7.24630288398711,9.49999999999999));
#548=CARTESIAN_POINT('',(26.2441791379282,-6.35333393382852,9.49999999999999));
#549=CARTESIAN_POINT('',(26.1030292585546,-5.90437491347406,9.49999999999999));
#550=CARTESIAN_POINT('',(25.8431550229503,-5.00009113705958,9.49999999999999));
#551=CARTESIAN_POINT('',(25.7244235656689,-4.54476844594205,9.49999999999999));
#552=CARTESIAN_POINT('',(25.5151678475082,-3.62736382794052,9.49999999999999));
#553=CARTESIAN_POINT('',(25.4246519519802,-3.16527993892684,9.49999999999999));
#554=CARTESIAN_POINT('',(25.3145813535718,-2.46810217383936,9.49999999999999));
#555=CARTESIAN_POINT('',(25.2821726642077,-2.2350058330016,9.49999999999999));
#556=CARTESIAN_POINT('',(25.2265608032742,-1.76772497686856,9.49999999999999));
#557=CARTESIAN_POINT('',(25.2033567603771,-1.5335405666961,9.49999999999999));
#558=CARTESIAN_POINT('',(25.1667780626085,-1.06587755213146,9.49999999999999));
#559=CARTESIAN_POINT('',(25.1533427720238,-0.832403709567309,9.49999999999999));
#560=CARTESIAN_POINT('',(25.1363723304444,-0.365097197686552,9.49999999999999));
#561=CARTESIAN_POINT('',(25.132837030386,-0.131264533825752,9.49999999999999));
#562=CARTESIAN_POINT('',(25.1357507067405,0.336274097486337,9.49999999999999));
#563=CARTESIAN_POINT('',(25.1421968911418,0.569980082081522,9.49999999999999));
#564=CARTESIAN_POINT('',(25.1649136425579,1.03691732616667,9.49999999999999));
#565=CARTESIAN_POINT('',(25.1811847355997,1.27014855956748,9.49999999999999));
#566=CARTESIAN_POINT('',(25.2322203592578,1.83577635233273,9.49999999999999));
#567=CARTESIAN_POINT('',(25.2719264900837,2.1677356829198,9.49999999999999));
#568=CARTESIAN_POINT('',(25.3690274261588,2.82904294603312,9.49999999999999));
#569=CARTESIAN_POINT('',(25.4264248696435,3.15839048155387,9.49999999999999));
#570=CARTESIAN_POINT('',(25.6222743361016,4.14309533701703,9.49999999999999));
#571=CARTESIAN_POINT('',(25.7842525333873,4.7938271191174,9.49999999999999));
#572=CARTESIAN_POINT('',(26.0634173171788,5.76718145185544,9.49999999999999));
#573=CARTESIAN_POINT('',(26.1638657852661,6.09489303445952,9.49999999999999));
#574=CARTESIAN_POINT('',(26.3747465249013,6.74715044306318,9.49999999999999));
#575=CARTESIAN_POINT('',(26.485179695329,7.07169598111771,9.49999999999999));
#576=CARTESIAN_POINT('',(26.7136658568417,7.71600141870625,9.49999999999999));
#577=CARTESIAN_POINT('',(26.831672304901,8.03577799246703,9.49999999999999));
#578=CARTESIAN_POINT('',(27.0744995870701,8.67261160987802,9.49999999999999));
#579=CARTESIAN_POINT('',(27.1993180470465,8.98966955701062,9.49999999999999));
#580=CARTESIAN_POINT('',(27.3269044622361,9.30558311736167,9.49999999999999));
#581=B_SPLINE_CURVE_WITH_KNOTS('',3,(#533,#534,#535,#536,#537,#538,#539,#540,#541,#542,#543,
#544,#545,#546,#547,#548,#549,#550,#551,#552,#553,#554,#555,#556,#557,#558,#559,#560,#561,#562,
#563,#564,#565,#566,#567,#568,#569,#570,#571,#572,#573,#574,#575,#576,#577,#578,#579,#580),
.UNSPECIFIED.,.F.,.F.,(4,2,2,2,2,2,2,2,2,2,2,2,2,2,2,2,2,2,2,2,2,2,2,4),(0.,0.694637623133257,
1.38928288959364,2.77880027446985,4.17629754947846,5.57372171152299,6.9880559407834,
8.40254735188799,9.81396052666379,11.2249258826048,12.6363091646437,13.3421715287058,
14.0479670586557,14.7493433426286,15.4507090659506,16.1518786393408,16.8530857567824,
17.8554925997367,18.8580490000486,20.867027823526,21.895229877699,22.923524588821,
23.9460134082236,24.9681481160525),.UNSPECIFIED.);
#582=EDGE_CURVE('E112',#483,#530,#581,.T.);
#583=ORIENTED_EDGE('',*,*,#582,.F.);
#584=EDGE_LOOP('',(#523,#524,#532,#583));
#585=FACE_BOUND('',#584,.T.);
#586=ADVANCED_FACE('F185',(#585),#522,.T.);
#587=CARTESIAN_POINT('',(0.,10.9696551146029,0.));
#588=DIRECTION('',(0.,0.866025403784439,0.5));
#589=DIRECTION('',(0.,-0.5,0.866025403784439));
#590=AXIS2_PLACEMENT_3D('',#587,#588,#589);
#591=PLANE('',#590);
#592=ORIENTED_EDGE('',*,*,#531,.T.);
#593=ORIENTED_EDGE('',*,*,#212,.F.);
#594=DIRECTION('',(1.,0.,0.));
#595=VECTOR('',#594,1.);
#596=CARTESIAN_POINT('',(0.,10.9696551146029,0.));
#597=LINE('',#596,#595);
#598=CARTESIAN_POINT('',(25.9824803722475,10.9696551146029,0.));
#599=VERTEX_POINT('',#598);
#600=EDGE_CURVE('E105',#599,#180,#597,.T.);
#601=ORIENTED_EDGE('',*,*,#600,.F.);
#602=CARTESIAN_POINT('',(25.9825470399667,5.4847120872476,9.5002));
#603=CARTESIAN_POINT('',(25.9129480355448,5.60528058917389,9.2913692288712));
#604=CARTESIAN_POINT('',(25.8465079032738,5.72629863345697,9.08175982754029));
#605=CARTESIAN_POINT('',(25.7208218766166,5.96930519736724,8.66086011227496));
#606=CARTESIAN_POINT('',(25.6615783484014,6.09129402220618,8.44956926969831));
#607=CARTESIAN_POINT('',(25.4957891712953,6.45922610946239,7.81229220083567));
#608=CARTESIAN_POINT('',(25.4014890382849,6.70662183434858,7.38379023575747));
#609=CARTESIAN_POINT('',(25.2909133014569,7.07683821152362,6.74255666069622));
#610=CARTESIAN_POINT('',(25.2594144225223,7.19855281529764,6.5317407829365));
#611=CARTESIAN_POINT('',(25.2065927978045,7.44254555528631,6.10913296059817));
#612=CARTESIAN_POINT('',(25.1852702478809,7.56482370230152,5.89734099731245));
#613=CARTESIAN_POINT('',(25.1533476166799,7.80958396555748,5.4734037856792));
#614=CARTESIAN_POINT('',(25.1427347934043,7.93206566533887,5.26125925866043));
#615=CARTESIAN_POINT('',(25.1324571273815,8.17714220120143,4.83677424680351));
#616=CARTESIAN_POINT('',(25.132791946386,8.29973703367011,4.62443376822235));
#617=CARTESIAN_POINT('',(25.1436479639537,8.5289310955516,4.22745800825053));
#618=CARTESIAN_POINT('',(25.1528448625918,8.63554650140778,4.04279470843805));
#619=CARTESIAN_POINT('',(25.1793399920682,8.84852796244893,3.67389999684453));
#620=CARTESIAN_POINT('',(25.1966387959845,8.95489399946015,3.48966861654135));
#621=CARTESIAN_POINT('',(25.2602790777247,9.27357996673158,2.93768832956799));
#622=CARTESIAN_POINT('',(25.3183564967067,9.48533580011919,2.57091646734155));
#623=CARTESIAN_POINT('',(25.4635506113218,9.91109368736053,1.83348217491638));
#624=CARTESIAN_POINT('',(25.551282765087,10.1250414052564,1.46291385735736));
#625=CARTESIAN_POINT('',(25.7503983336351,10.5497463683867,0.727303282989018));
#626=CARTESIAN_POINT('',(25.8617349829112,10.7605090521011,0.362251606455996));
#627=CARTESIAN_POINT('',(25.9825470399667,10.9697705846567,-0.000200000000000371));
#628=B_SPLINE_CURVE_WITH_KNOTS('',3,(#602,#603,#604,#605,#606,#607,#608,#609,#610,#611,#612,
#613,#614,#615,#616,#617,#618,#619,#620,#621,#622,#623,#624,#625,#626,#627),.UNSPECIFIED.,.F.,
.F.,(4,2,2,2,2,2,2,2,2,2,2,2,4),(0.,0.752880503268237,1.50600787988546,3.01546870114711,
3.75167336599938,4.48789219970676,5.22323407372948,5.95855322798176,6.59868084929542,
7.23885375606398,8.52010929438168,9.82978009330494,11.1368800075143),.UNSPECIFIED.);
#629=EDGE_CURVE('E110',#530,#599,#628,.T.);
#630=ORIENTED_EDGE('',*,*,#629,.F.);
#631=EDGE_LOOP('',(#592,#593,#601,#630));
#632=FACE_BOUND('',#631,.T.);
#633=ADVANCED_FACE('F136',(#632),#591,.T.);
#634=CARTESIAN_POINT('',(0.,5.48482755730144,-9.5));
#635=DIRECTION('',(0.,0.866025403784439,-0.5));
#636=DIRECTION('',(0.,0.5,0.866025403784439));
#637=AXIS2_PLACEMENT_3D('',#634,#635,#636);
#638=PLANE('',#637);
#639=ORIENTED_EDGE('',*,*,#600,.T.);
#640=ORIENTED_EDGE('',*,*,#181,.F.);
#641=DIRECTION('',(1.,0.,0.));
#642=VECTOR('',#641,1.);
#643=CARTESIAN_POINT('',(0.,5.48482755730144,-9.5));
#644=LINE('',#643,#642);
#645=CARTESIAN_POINT('',(25.9824803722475,5.48482755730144,-9.5));
#646=VERTEX_POINT('',#645);
#647=EDGE_CURVE('E60',#646,#149,#644,.T.);
#648=ORIENTED_EDGE('',*,*,#647,.F.);
#649=CARTESIAN_POINT('',(25.9825470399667,10.9697705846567,0.000199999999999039));
#650=CARTESIAN_POINT('',(25.9129480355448,10.8492020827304,-0.208630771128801));
#651=CARTESIAN_POINT('',(25.8465079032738,10.7281840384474,-0.418240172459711));
#652=CARTESIAN_POINT('',(25.7208218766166,10.4851774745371,-0.83913988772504));
#653=CARTESIAN_POINT('',(25.6615783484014,10.3631886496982,-1.05043073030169));
#654=CARTESIAN_POINT('',(25.4957891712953,9.99525656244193,-1.68770779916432));
#655=CARTESIAN_POINT('',(25.4014890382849,9.74786083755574,-2.11620976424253));
#656=CARTESIAN_POINT('',(25.2909133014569,9.37764446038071,-2.75744333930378));
#657=CARTESIAN_POINT('',(25.2594144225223,9.25592985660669,-2.96825921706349));
#658=CARTESIAN_POINT('',(25.2065927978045,9.01193711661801,-3.39086703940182));
#659=CARTESIAN_POINT('',(25.1852702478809,8.8896589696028,-3.60265900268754));
#660=CARTESIAN_POINT('',(25.1533476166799,8.64489870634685,-4.0265962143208));
#661=CARTESIAN_POINT('',(25.1427347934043,8.52241700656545,-4.23874074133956));
#662=CARTESIAN_POINT('',(25.1324571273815,8.27734047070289,-4.66322575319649));
#663=CARTESIAN_POINT('',(25.132791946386,8.15474563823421,-4.87556623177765));
#664=CARTESIAN_POINT('',(25.1436479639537,7.92555157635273,-5.27254199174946));
#665=CARTESIAN_POINT('',(25.1528448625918,7.81893617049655,-5.45720529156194));
#666=CARTESIAN_POINT('',(25.1793399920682,7.6059547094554,-5.82610000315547));
#667=CARTESIAN_POINT('',(25.1966387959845,7.49958867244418,-6.01033138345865));
#668=CARTESIAN_POINT('',(25.2602790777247,7.18090270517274,-6.56231167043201));
#669=CARTESIAN_POINT('',(25.3183564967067,6.96914687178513,-6.92908353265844));
#670=CARTESIAN_POINT('',(25.4635506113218,6.5433889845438,-7.66651782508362));
#671=CARTESIAN_POINT('',(25.551282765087,6.32944126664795,-8.03708614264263));
#672=CARTESIAN_POINT('',(25.7503983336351,5.90473630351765,-8.77269671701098));
#673=CARTESIAN_POINT('',(25.8617349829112,5.69397361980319,-9.137748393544));
#674=CARTESIAN_POINT('',(25.9825470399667,5.4847120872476,-9.5002));
#675=B_SPLINE_CURVE_WITH_KNOTS('',3,(#649,#650,#651,#652,#653,#654,#655,#656,#657,#658,#659,
#660,#661,#662,#663,#664,#665,#666,#667,#668,#669,#670,#671,#672,#673,#674),.UNSPECIFIED.,.F.,
.F.,(4,2,2,2,2,2,2,2,2,2,2,2,4),(0.,0.75288050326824,1.50600787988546,3.01546870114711,
3.75167336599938,4.48789219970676,5.22323407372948,5.95855322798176,6.59868084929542,
7.23885375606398,8.52010929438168,9.82978009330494,11.1368800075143),.UNSPECIFIED.);
#676=EDGE_CURVE('E95',#599,#646,#675,.T.);
#677=ORIENTED_EDGE('',*,*,#676,.F.);
#678=EDGE_LOOP('',(#639,#640,#648,#677));
#679=FACE_BOUND('',#678,.T.);
#680=ADVANCED_FACE('F100',(#679),#638,.T.);
#681=CARTESIAN_POINT('',(0.,-5.48482755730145,-9.5));
#682=DIRECTION('',(0.,0.,-1.));
#683=DIRECTION('',(0.,1.,0.));
#684=AXIS2_PLACEMENT_3D('',#681,#682,#683);
#685=PLANE('',#684);
#686=ORIENTED_EDGE('',*,*,#647,.T.);
#687=ORIENTED_EDGE('',*,*,#150,.F.);
#688=ORIENTED_EDGE('',*,*,#428,.F.);
#689=CARTESIAN_POINT('',(29.6721745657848,-14.530424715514,-9.5));
#690=CARTESIAN_POINT('',(29.5714312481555,-14.3219433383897,-9.5));
#691=CARTESIAN_POINT('',(29.4712106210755,-14.1132095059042,-9.5));
#692=CARTESIAN_POINT('',(29.2719347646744,-13.6951836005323,-9.5));
#693=CARTESIAN_POINT('',(29.1728795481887,-13.4858915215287,-9.5));
#694=CARTESIAN_POINT('',(28.8776132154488,-12.8570363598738,-9.5));
#695=CARTESIAN_POINT('',(28.6833343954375,-12.4365624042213,-9.5));
#696=CARTESIAN_POINT('',(28.3000719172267,-11.5902889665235,-9.5));
#697=CARTESIAN_POINT('',(28.1111250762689,-11.1644727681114,-9.5));
#698=CARTESIAN_POINT('',(27.7413671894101,-10.3093352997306,-9.5));
#699=CARTESIAN_POINT('',(27.5605557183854,-9.88001421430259,-9.5));
#700=CARTESIAN_POINT('',(27.2071219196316,-9.01192846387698,-9.5));
#701=CARTESIAN_POINT('',(27.0346251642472,-8.573112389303,-9.5));
#702=CARTESIAN_POINT('',(26.7031815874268,-7.69029988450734,-9.5));
#703=CARTESIAN_POINT('',(26.5442362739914,-7.24630288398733,-9.5));
#704=CARTESIAN_POINT('',(26.2441791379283,-6.3533339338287,-9.5));
#705=CARTESIAN_POINT('',(26.1030292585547,-5.90437491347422,-9.5));
#706=CARTESIAN_POINT('',(25.8431550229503,-5.0000911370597,-9.5));
#707=CARTESIAN_POINT('',(25.724423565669,-4.54476844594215,-9.5));
#708=CARTESIAN_POINT('',(25.5151678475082,-3.62736382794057,-9.5));
#709=CARTESIAN_POINT('',(25.4246519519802,-3.16527993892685,-9.5));
#710=CARTESIAN_POINT('',(25.3145813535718,-2.46810217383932,-9.5));
#711=CARTESIAN_POINT('',(25.2821726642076,-2.23500583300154,-9.5));
#712=CARTESIAN_POINT('',(25.2265608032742,-1.76772497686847,-9.5));
#713=CARTESIAN_POINT('',(25.2033567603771,-1.533540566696,-9.5));
#714=CARTESIAN_POINT('',(25.1667780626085,-1.06587755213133,-9.5));
#715=CARTESIAN_POINT('',(25.1533427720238,-0.832403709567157,-9.5));
#716=CARTESIAN_POINT('',(25.1363723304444,-0.365097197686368,-9.5));
#717=CARTESIAN_POINT('',(25.132837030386,-0.131264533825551,-9.5));
#718=CARTESIAN_POINT('',(25.1357507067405,0.33627409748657,-9.5));
#719=CARTESIAN_POINT('',(25.1421968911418,0.569980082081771,-9.5));
#720=CARTESIAN_POINT('',(25.1649136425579,1.03691732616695,-9.5));
#721=CARTESIAN_POINT('',(25.1811847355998,1.27014855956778,-9.5));
#722=CARTESIAN_POINT('',(25.2322203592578,1.83577635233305,-9.5));
#723=CARTESIAN_POINT('',(25.2719264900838,2.16773568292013,-9.5));
#724=CARTESIAN_POINT('',(25.3690274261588,2.82904294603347,-9.5));
#725=CARTESIAN_POINT('',(25.4264248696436,3.15839048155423,-9.5));
#726=CARTESIAN_POINT('',(25.6222743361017,4.14309533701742,-9.5));
#727=CARTESIAN_POINT('',(25.7842525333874,4.7938271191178,-9.5));
#728=CARTESIAN_POINT('',(26.0634173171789,5.76718145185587,-9.5));
#729=CARTESIAN_POINT('',(26.1638657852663,6.09489303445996,-9.5));
#730=CARTESIAN_POINT('',(26.3747465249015,6.74715044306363,-9.5));
#731=CARTESIAN_POINT('',(26.4851796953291,7.07169598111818,-9.5));
#732=CARTESIAN_POINT('',(26.7136658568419,7.71600141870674,-9.5));
#733=CARTESIAN_POINT('',(26.8316723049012,8.03577799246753,-9.5));
#734=CARTESIAN_POINT('',(27.0744995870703,8.67261160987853,-9.5));
#735=CARTESIAN_POINT('',(27.1993180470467,8.98966955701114,-9.5));
#736=CARTESIAN_POINT('',(27.3269044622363,9.3055831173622,-9.5));
#737=B_SPLINE_CURVE_WITH_KNOTS('',3,(#689,#690,#691,#692,#693,#694,#695,#696,#697,#698,#699,
#700,#701,#702,#703,#704,#705,#706,#707,#708,#709,#710,#711,#712,#713,#714,#715,#716,#717,#718,
#719,#720,#721,#722,#723,#724,#725,#726,#727,#728,#729,#730,#731,#732,#733,#734,#735,#736),
.UNSPECIFIED.,.F.,.F.,(4,2,2,2,2,2,2,2,2,2,2,2,2,2,2,2,2,2,2,2,2,2,2,4),(0.,0.694637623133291,
1.38928288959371,2.77880027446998,4.17629754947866,5.57372171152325,6.98805594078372,
8.40254735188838,9.81396052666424,11.2249258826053,12.6363091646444,13.3421715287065,
14.0479670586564,14.7493433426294,15.4507090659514,16.1518786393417,16.8530857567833,
17.8554925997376,18.8580490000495,20.867027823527,21.8952298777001,22.9235245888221,
23.9460134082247,24.9681481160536),.UNSPECIFIED.);
#738=EDGE_CURVE('E90',#646,#427,#737,.F.);
#739=ORIENTED_EDGE('',*,*,#738,.F.);
#740=EDGE_LOOP('',(#686,#687,#688,#739));
#741=FACE_BOUND('',#740,.T.);
#742=ADVANCED_FACE('F91',(#741),#685,.T.);
#743=CARTESIAN_POINT('',(0.,0.,0.));
#744=DIRECTION('',(-1.,0.,0.));
#745=DIRECTION('',(0.,0.,1.));
#746=AXIS2_PLACEMENT_3D('',#743,#744,#745);
#747=PLANE('',#746);
#748=CARTESIAN_POINT('',(0.,0.,0.));
#749=DIRECTION('',(1.,0.,0.));
#750=DIRECTION('',(0.,0.,-1.));
#751=AXIS2_PLACEMENT_3D('',#748,#749,#750);
#752=CIRCLE('',#751,5.);
#753=CARTESIAN_POINT('',(0.,0.,-5.));
#754=VERTEX_POINT('',#753);
#755=EDGE_CURVE('E277',#754,#754,#752,.T.);
#756=ORIENTED_EDGE('',*,*,#755,.F.);
#757=EDGE_LOOP('',(#756));
#758=FACE_BOUND('',#757,.T.);
#759=ADVANCED_FACE('F36',(#758),#747,.T.);
#760=CARTESIAN_POINT('',(1.,0.,0.));
#761=DIRECTION('',(1.,0.,0.));
#762=DIRECTION('',(0.,0.,-1.));
#763=AXIS2_PLACEMENT_3D('',#760,#761,#762);
#764=CONICAL_SURFACE('',#763,6.,0.785398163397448);
#765=ORIENTED_EDGE('',*,*,#755,.T.);
#766=EDGE_LOOP('',(#765));
#767=FACE_BOUND('',#766,.T.);
#768=CARTESIAN_POINT('',(1.,0.,0.));
#769=DIRECTION('',(1.,0.,0.));
#770=DIRECTION('',(0.,0.,-1.));
#771=AXIS2_PLACEMENT_3D('',#768,#769,#770);
#772=CIRCLE('',#771,6.);
#773=CARTESIAN_POINT('',(1.,0.,-6.));
#774=VERTEX_POINT('',#773);
#775=EDGE_CURVE('E275',#774,#774,#772,.T.);
#776=ORIENTED_EDGE('',*,*,#775,.F.);
#777=EDGE_LOOP('',(#776));
#778=FACE_BOUND('',#777,.T.);
#779=ADVANCED_FACE('F398',(#767,#778),#764,.T.);
#780=CARTESIAN_POINT('',(0.,0.,0.));
#781=DIRECTION('',(1.,0.,0.));
#782=DIRECTION('',(0.,0.,-1.));
#783=AXIS2_PLACEMENT_3D('',#780,#781,#782);
#784=CYLINDRICAL_SURFACE('',#783,6.);
#785=ORIENTED_EDGE('',*,*,#775,.T.);
#786=EDGE_LOOP('',(#785));
#787=FACE_BOUND('',#786,.T.);
#788=CARTESIAN_POINT('',(22.,0.,0.));
#789=DIRECTION('',(1.,0.,0.));
#790=DIRECTION('',(0.,0.,-1.));
#791=AXIS2_PLACEMENT_3D('',#788,#789,#790);
#792=CIRCLE('',#791,6.);
#793=CARTESIAN_POINT('',(22.,0.,-6.));
#794=VERTEX_POINT('',#793);
#795=EDGE_CURVE('E272',#794,#794,#792,.T.);
#796=ORIENTED_EDGE('',*,*,#795,.F.);
#797=EDGE_LOOP('',(#796));
#798=FACE_BOUND('',#797,.T.);
#799=ADVANCED_FACE('F407',(#787,#798),#784,.T.);
#800=CARTESIAN_POINT('',(22.,6.,0.));
#801=DIRECTION('',(1.,0.,0.));
#802=DIRECTION('',(0.,0.,-1.));
#803=AXIS2_PLACEMENT_3D('',#800,#801,#802);
#804=PLANE('',#803);
#805=ORIENTED_EDGE('',*,*,#795,.T.);
#806=EDGE_LOOP('',(#805));
#807=FACE_BOUND('',#806,.T.);
#808=CARTESIAN_POINT('',(22.,0.,0.));
#809=DIRECTION('',(1.,0.,0.));
#810=DIRECTION('',(0.,0.,-1.));
#811=AXIS2_PLACEMENT_3D('',#808,#809,#810);
#812=CIRCLE('',#811,5.);
#813=CARTESIAN_POINT('',(22.,0.,-5.));
#814=VERTEX_POINT('',#813);
#815=EDGE_CURVE('E269',#814,#814,#812,.T.);
#816=ORIENTED_EDGE('',*,*,#815,.F.);
#817=EDGE_LOOP('',(#816));
#818=FACE_BOUND('',#817,.T.);
#819=ADVANCED_FACE('F415',(#807,#818),#804,.T.);
#820=CARTESIAN_POINT('',(0.,0.,0.));
#821=DIRECTION('',(1.,0.,0.));
#822=DIRECTION('',(0.,0.,-1.));
#823=AXIS2_PLACEMENT_3D('',#820,#821,#822);
#824=CYLINDRICAL_SURFACE('',#823,5.);
#825=ORIENTED_EDGE('',*,*,#815,.T.);
#826=EDGE_LOOP('',(#825));
#827=FACE_BOUND('',#826,.T.);
#828=CARTESIAN_POINT('',(25.,0.,0.));
#829=DIRECTION('',(1.,0.,0.));
#830=DIRECTION('',(0.,0.,-1.));
#831=AXIS2_PLACEMENT_3D('',#828,#829,#830);
#832=CIRCLE('',#831,5.);
#833=CARTESIAN_POINT('',(25.,0.,-5.));
#834=VERTEX_POINT('',#833);
#835=EDGE_CURVE('E266',#834,#834,#832,.T.);
#836=ORIENTED_EDGE('',*,*,#835,.F.);
#837=EDGE_LOOP('',(#836));
#838=FACE_BOUND('',#837,.T.);
#839=ADVANCED_FACE('F425',(#827,#838),#824,.T.);
#840=CARTESIAN_POINT('',(25.,5.,0.));
#841=DIRECTION('',(-1.,0.,0.));
#842=DIRECTION('',(0.,0.,1.));
#843=AXIS2_PLACEMENT_3D('',#840,#841,#842);
#844=PLANE('',#843);
#845=ORIENTED_EDGE('',*,*,#835,.T.);
#846=EDGE_LOOP('',(#845));
#847=FACE_BOUND('',#846,.T.);
#848=CARTESIAN_POINT('',(25.,0.,0.));
#849=DIRECTION('',(1.,0.,0.));
#850=DIRECTION('',(0.,0.,-1.));
#851=AXIS2_PLACEMENT_3D('',#848,#849,#850);
#852=CIRCLE('',#851,9.26794919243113);
#853=CARTESIAN_POINT('',(25.,0.,-9.26794919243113));
#854=VERTEX_POINT('',#853);
#855=EDGE_CURVE('E263',#854,#854,#852,.T.);
#856=ORIENTED_EDGE('',*,*,#855,.F.);
#857=EDGE_LOOP('',(#856));
#858=FACE_BOUND('',#857,.T.);
#859=ADVANCED_FACE('F367',(#847,#858),#844,.T.);
#860=CARTESIAN_POINT('',(26.,0.,0.));
#861=DIRECTION('',(1.,0.,0.));
#862=DIRECTION('',(0.,0.,-1.));
#863=AXIS2_PLACEMENT_3D('',#860,#861,#862);
#864=CONICAL_SURFACE('',#863,11.,1.04719755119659);
#865=ORIENTED_EDGE('',*,*,#855,.T.);
#866=EDGE_LOOP('',(#865));
#867=FACE_BOUND('',#866,.T.);
#868=ORIENTED_EDGE('',*,*,#738,.T.);
#869=ORIENTED_EDGE('',*,*,#466,.T.);
#870=ORIENTED_EDGE('',*,*,#513,.T.);
#871=ORIENTED_EDGE('',*,*,#582,.T.);
#872=ORIENTED_EDGE('',*,*,#629,.T.);
#873=ORIENTED_EDGE('',*,*,#676,.T.);
#874=EDGE_LOOP('',(#868,#869,#870,#871,#872,#873));
#875=FACE_BOUND('',#874,.T.);
#876=ADVANCED_FACE('F108',(#867,#875),#864,.T.);
#877=CLOSED_SHELL('',(#267,#287,#307,#327,#347,#367,#387,#407,#416,#470,#517,#586,#633,#680,
#742,#759,#779,#799,#819,#839,#859,#876));
#878=MANIFOLD_SOLID_BREP('B2',#877);
#879=ADVANCED_BREP_SHAPE_REPRESENTATION('',(#18,#878),#14);
#880=SHAPE_DEFINITION_REPRESENTATION(#9,#879);
ENDSEC;
END-ISO-10303-21;
